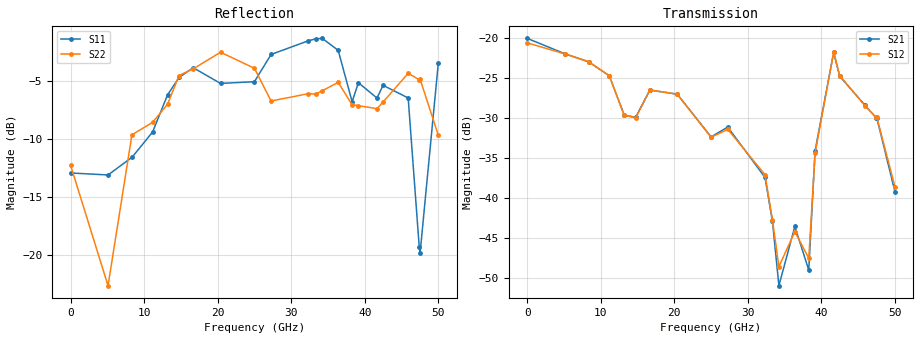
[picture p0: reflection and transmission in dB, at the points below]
!Keysight Technologies,N5245B,MY58422270,A.16.20.02
!Date: Thursday, March 05, 2026 01:23:44
!Correction: S11(C  2-Port  )
!S21(C  2-Port  )
!S12(C  2-Port  )
!S22(C  2-Port  )
!S2P File: Measurements: S11, S21, S12, S22:
# Hz S  dB  R 50
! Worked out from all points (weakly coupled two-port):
!   3201 points, 10 MHz to 50 GHz, reference 50 ohm
!   highest |S21| = -20.10 dB at 10 MHz (marker M1); lowest = -50.9 dB at 34.22 GHz (marker M2)
!   lowest |S11| = -19.8 dB at 47.53 GHz (marker M3), VSWR 1.23, Z = 46 + j9.04 ohm
!   |S11| at or under -10 dB: start of sweep to 10.13 GHz; 11.36 GHz to 11.92 GHz (567.8 MHz wide, 4.88 % of centre); 46.67 GHz to 48.27 GHz (1.605 GHz wide, 3.38 % of centre)
!   |S22| runs from -22.6 to -2.5 dB; largest |S21 - S12| = 0.0078
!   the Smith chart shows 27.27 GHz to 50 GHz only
!   S11 on the Smith chart (normalised r, x): 27.27 GHz: 0.18, +0.37; 32.33 GHz: 0.43, +1.88; 36.39 GHz: 2.32, -3.28; 42.49 GHz: 0.98, -1.26; 47.41 GHz: 0.84, +0.13; 50 GHz: 0.61, -1.35
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1e7  -12.94 -3.8  -20.10 4.0  -20.66 4.1  -12.28 29.0
5.102731e9  -13.11 -126.2  -22.01 160.7  -22.03 160.9  -22.62 -132.0
8.352081e9  -11.60 174.7  -23.02 25.2  -23.01 25.3  -9.66 -156.9
1.116402e10  -9.42 106.4  -24.77 -83.4  -24.74 -83.2  -8.59 90.8
1.319486e10  -6.23 63.2  -29.66 -141.7  -29.69 -141.3  -7.04 -20.0
1.475705e10  -4.74 13.3  -29.94 -156.3  -29.99 -156.1  -4.57 -88.5
1.667854e10  -3.90 -43.8  -26.54 157.3  -26.53 157.4  -4.00 -139.6
2.039655e10  -5.25 -121.4  -27.05 40.5  -27.05 40.4  -2.57 155.5
2.5005e10  -5.10 179.8  -32.37 -64.2  -32.43 -64.1  -3.95 71.3
2.727017e10  -2.76 138.0  -31.15 -115.3  -31.43 -114.0  -6.76 30.7
3.233166e10  -1.59 54.2  -37.42 45.1  -37.08 46.2  -6.13 -104.1
3.334708e10  -1.42 36.1  -42.90 4.2  -42.70 1.8  -6.17 -126.3
3.422191e10  -1.38 20.5  -50.91 -82.3  -48.54 -73.0  -5.88 -144.4
3.639335e10  -2.41 -23.4  -43.53 114.7  -44.17 115.8  -5.16 174.0
3.828359e10  -6.81 -22.2  -48.97 -89.9  -47.49 106.8  -7.08 139.1
3.91428e10  -5.19 -31.8  -34.10 97.8  -34.41 98.7  -7.16 138.1
4.167354e10  -6.51 -52.7  -21.84 -58.7  -21.83 -58.8  -7.42 117.6
4.248588e10  -5.41 -58.4  -24.82 -121.0  -24.73 -121.1  -6.85 113.2
4.590707e10  -6.50 -117.6  -28.40 55.6  -28.49 53.9  -4.38 63.1
4.740677e10  -19.26 137.2  -29.98 -1.4  -29.90 -2.3  -4.93 42.8
4.753174e10  -19.78 108.6  -30.02 -3.5  -29.91 -3.8  -4.89 41.4
5e10  -3.53 -66.2  -39.19 -131.6  -38.59 -127.4  -9.70 2.5
